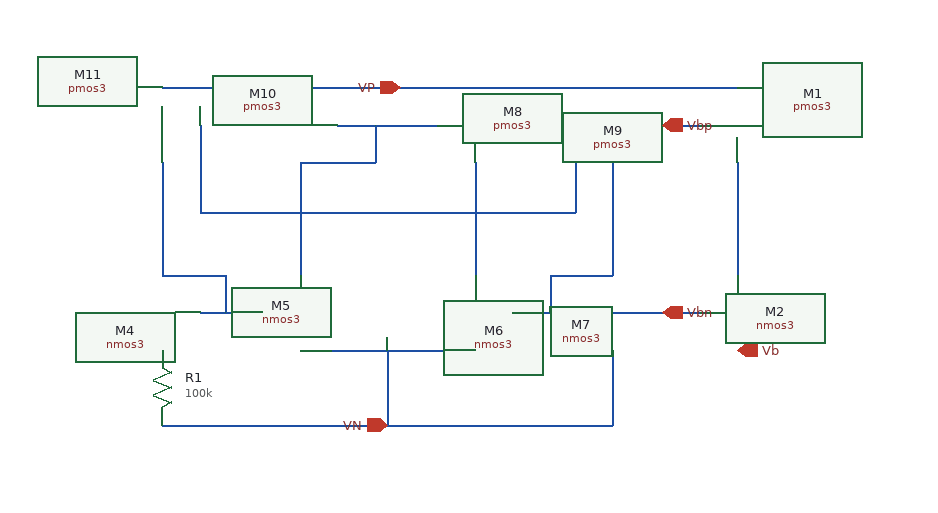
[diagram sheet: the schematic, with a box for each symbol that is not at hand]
v {xschem version=3.4.3 file_version=1.2
}
G {}
K {}
V {}
S {}
E {}
N -160 40 -110 40 {
lab=#net1}
N -140 10 -140 40 {
lab=#net1}
N -190 10 -140 10 {
lab=#net1}
N 90 40 140 40 {
lab=Vbn}
N 120 10 120 40 {
lab=Vbn}
N 120 10 170 10 {
lab=Vbn}
N -80 70 60 70 {
lab=VN}
N -190 130 -20 130 {
lab=VN}
N -190 -80 -190 10 {
lab=#net1}
N -50 -110 30 -110 {
lab=#net2}
N -20 -110 -20 -80 {
lab=#net2}
N -80 -80 -20 -80 {
lab=#net2}
N -80 -80 -80 10 {
lab=#net2}
N 60 -80 60 10 {
lab=Vbn}
N 170 -80 170 10 {
lab=Vbn}
N 140 -110 140 -40 {
lab=Vbn}
N 60 -40 140 -40 {
lab=Vbn}
N -160 -40 60 -40 {
lab=Vbn}
N -160 -110 -160 -40 {
lab=Vbn}
N -190 -140 -80 -140 {
lab=VP}
N -80 -140 -20 -140 {
lab=VP}
N -20 -140 60 -140 {
lab=VP}
N 60 -140 170 -140 {
lab=VP}
N -20 130 170 130 {
lab=VN}
N 170 70 170 130 {
lab=VN}
N -10 70 -10 130 {
lab=VN}
N 140 -110 240 -110 {
lab=Vbn}
N 170 -140 270 -140 {
lab=VP}
N 140 40 240 40 {
lab=Vbn}
N 270 -80 270 10 {
lab=#net3}
C {madvlsi/nmos3.sym} -190 40 0 1 {name=M4
L=0.5
W=12
body=GND
nf=1
mult=8
ad="'int((nf+1)/2) * W/nf * 0.29'" 
pd="'2*int((nf+1)/2) * (W/nf + 0.29)'"
as="'int((nf+2)/2) * W/nf * 0.29'" 
ps="'2*int((nf+2)/2) * (W/nf + 0.29)'"
nrd="'0.29 / W'" nrs="'0.29 / W'"
sa=0 sb=0 sd=0
model=nfet_01v8
spiceprefix=X
}
C {madvlsi/nmos3.sym} -80 40 0 0 {name=M5
L=0.5
W=12
body=GND
nf=1
mult=1
ad="'int((nf+1)/2) * W/nf * 0.29'" 
pd="'2*int((nf+1)/2) * (W/nf + 0.29)'"
as="'int((nf+2)/2) * W/nf * 0.29'" 
ps="'2*int((nf+2)/2) * (W/nf + 0.29)'"
nrd="'0.29 / W'" nrs="'0.29 / W'"
sa=0 sb=0 sd=0
model=nfet_01v8
spiceprefix=X
}
C {madvlsi/nmos3.sym} 60 40 0 1 {name=M6
L=0.5
W=12
body=GND
nf=1
mult=1
ad="'int((nf+1)/2) * W/nf * 0.29'" 
pd="'2*int((nf+1)/2) * (W/nf + 0.29)'"
as="'int((nf+2)/2) * W/nf * 0.29'" 
ps="'2*int((nf+2)/2) * (W/nf + 0.29)'"
nrd="'0.29 / W'" nrs="'0.29 / W'"
sa=0 sb=0 sd=0
model=nfet_01v8
spiceprefix=X
}
C {madvlsi/nmos3.sym} 170 40 0 0 {name=M7
L=0.5
W=12
body=GND
nf=1
mult=1
ad="'int((nf+1)/2) * W/nf * 0.29'" 
pd="'2*int((nf+1)/2) * (W/nf + 0.29)'"
as="'int((nf+2)/2) * W/nf * 0.29'" 
ps="'2*int((nf+2)/2) * (W/nf + 0.29)'"
nrd="'0.29 / W'" nrs="'0.29 / W'"
sa=0 sb=0 sd=0
model=nfet_01v8
spiceprefix=X
}
C {madvlsi/resistor.sym} -190 100 0 0 {name=R1
value=100k
m=1}
C {madvlsi/pmos3.sym} 60 -110 0 0 {name=M8
L=0.5
W=12
body=VDD
nf=1
mult=1
ad="'int((nf+1)/2) * W/nf * 0.29'" 
pd="'2*int((nf+1)/2) * (W/nf + 0.29)'"
as="'int((nf+2)/2) * W/nf * 0.29'" 
ps="'2*int((nf+2)/2) * (W/nf + 0.29)'"
nrd="'0.29 / W'" nrs="'0.29 / W'"
sa=0 sb=0 sd=0
model=pfet_01v8
spiceprefix=X
}
C {madvlsi/pmos3.sym} 170 -110 0 0 {name=M9
L=0.5
W=12
body=VDD
nf=1
mult=1
ad="'int((nf+1)/2) * W/nf * 0.29'" 
pd="'2*int((nf+1)/2) * (W/nf + 0.29)'"
as="'int((nf+2)/2) * W/nf * 0.29'" 
ps="'2*int((nf+2)/2) * (W/nf + 0.29)'"
nrd="'0.29 / W'" nrs="'0.29 / W'"
sa=0 sb=0 sd=0
model=pfet_01v8
spiceprefix=X
}
C {madvlsi/pmos3.sym} -80 -110 0 1 {name=M10
L=0.5
W=12
body=VDD
nf=1
mult=1
ad="'int((nf+1)/2) * W/nf * 0.29'" 
pd="'2*int((nf+1)/2) * (W/nf + 0.29)'"
as="'int((nf+2)/2) * W/nf * 0.29'" 
ps="'2*int((nf+2)/2) * (W/nf + 0.29)'"
nrd="'0.29 / W'" nrs="'0.29 / W'"
sa=0 sb=0 sd=0
model=pfet_01v8
spiceprefix=X
}
C {madvlsi/pmos3.sym} -190 -110 0 1 {name=M11
L=0.5
W=12
body=VDD
nf=1
mult=1
ad="'int((nf+1)/2) * W/nf * 0.29'" 
pd="'2*int((nf+1)/2) * (W/nf + 0.29)'"
as="'int((nf+2)/2) * W/nf * 0.29'" 
ps="'2*int((nf+2)/2) * (W/nf + 0.29)'"
nrd="'0.29 / W'" nrs="'0.29 / W'"
sa=0 sb=0 sd=0
model=pfet_01v8
spiceprefix=X
}
C {devices/iopin.sym} 0 -140 3 0 {name=p1 lab=VP}
C {devices/iopin.sym} -10 130 1 0 {name=p2 lab=VN}
C {madvlsi/pmos3.sym} 270 -110 0 0 {name=M1
L=0.5
W=12
body=VDD
nf=1
mult=1
ad="'int((nf+1)/2) * W/nf * 0.29'" 
pd="'2*int((nf+1)/2) * (W/nf + 0.29)'"
as="'int((nf+2)/2) * W/nf * 0.29'" 
ps="'2*int((nf+2)/2) * (W/nf + 0.29)'"
nrd="'0.29 / W'" nrs="'0.29 / W'"
sa=0 sb=0 sd=0
model=pfet_01v8
spiceprefix=X
}
C {devices/opin.sym} 270 70 1 0 {name=p4 lab=Vb}
C {madvlsi/nmos3.sym} 270 40 0 0 {name=M2
L=0.5
W=12
body=GND
nf=1
mult=1
ad="'int((nf+1)/2) * W/nf * 0.29'" 
pd="'2*int((nf+1)/2) * (W/nf + 0.29)'"
as="'int((nf+2)/2) * W/nf * 0.29'" 
ps="'2*int((nf+2)/2) * (W/nf + 0.29)'"
nrd="'0.29 / W'" nrs="'0.29 / W'"
sa=0 sb=0 sd=0
model=nfet_01v8
spiceprefix=X
}
C {devices/opin.sym} 210 40 3 0 {name=p3 lab=Vbn}
C {devices/opin.sym} 210 -110 1 0 {name=p5 lab=Vbp}
